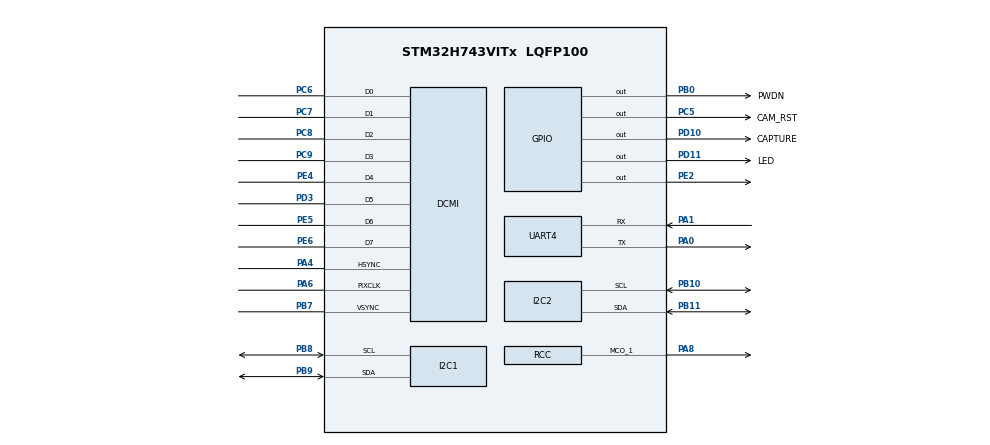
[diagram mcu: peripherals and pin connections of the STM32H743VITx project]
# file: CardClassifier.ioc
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CORTEX_M7.CPU_DCache=Enabled
CORTEX_M7.CPU_ICache=Enabled
CORTEX_M7.default_mode_Activation=1
DCMI.PCKPolarity=DCMI_PCKPOLARITY_RISING
DCMI.VSPolarity=DCMI_VSPOLARITY_HIGH
Dma.DCMI.0.Direction=DMA_PERIPH_TO_MEMORY
Dma.DCMI.0.EventEnable=DISABLE
Dma.DCMI.0.FIFOMode=DMA_FIFOMODE_DISABLE
Dma.DCMI.0.Instance=DMA1_Stream0
Dma.DCMI.0.MemDataAlignment=DMA_MDATAALIGN_WORD
Dma.DCMI.0.MemInc=DMA_MINC_ENABLE
Dma.DCMI.0.Mode=DMA_NORMAL
Dma.DCMI.0.PeriphDataAlignment=DMA_PDATAALIGN_WORD
Dma.DCMI.0.PeriphInc=DMA_PINC_DISABLE
Dma.DCMI.0.Polarity=HAL_DMAMUX_REQ_GEN_RISING
Dma.DCMI.0.Priority=DMA_PRIORITY_VERY_HIGH
Dma.DCMI.0.RequestNumber=1
Dma.DCMI.0.SignalID=NONE
Dma.DCMI.0.SyncEnable=DISABLE
Dma.DCMI.0.SyncPolarity=HAL_DMAMUX_SYNC_NO_EVENT
Dma.DCMI.0.SyncRequestNumber=1
Dma.DCMI.0.SyncSignalID=NONE
Dma.Request0=DCMI
I2C1.Timing=0x00707CBB
I2C2.Timing=0x00707CBB
Mcu.Family=STM32H7
Mcu.Name=STM32H743VITx
Mcu.Package=LQFP100
NVIC.DCMI_IRQn=true\:0\:0\:false\:false\:true\:true\:true\:true
NVIC.DMA1_Stream0_IRQn=true\:0\:0\:false\:false\:true\:false\:true\:true
NVIC.PriorityGroup=NVIC_PRIORITYGROUP_4
PA0.Mode=Asynchronous
PA0.Signal=UART4_TX
PA1.Mode=Asynchronous
PA1.Signal=UART4_RX
PA4.GPIO_PuPd=GPIO_PULLDOWN
PA4.GPIO_Speed=GPIO_SPEED_FREQ_VERY_HIGH
PA4.Mode=Slave_8_bits_External_Synchro
PA4.Signal=DCMI_HSYNC
PA6.GPIO_PuPd=GPIO_PULLDOWN
PA6.GPIO_Speed=GPIO_SPEED_FREQ_VERY_HIGH
PA6.Mode=Slave_8_bits_External_Synchro
PA6.Signal=DCMI_PIXCLK
PA8.Mode=Clock-out-1
PA8.Signal=RCC_MCO_1
PB0.GPIO_Label=PWDN
PB0.PinState=GPIO_PIN_SET
PB0.Signal=GPIO_Output
PB10.GPIO_Pu=GPIO_NOPULL
PB10.Mode=I2C
PB10.Signal=I2C2_SCL
PB11.GPIO_Pu=GPIO_NOPULL
PB11.Mode=I2C
PB11.Signal=I2C2_SDA
PB7.GPIO_PuPd=GPIO_PULLDOWN
PB7.GPIO_Speed=GPIO_SPEED_FREQ_VERY_HIGH
PB7.Mode=Slave_8_bits_External_Synchro
PB7.Signal=DCMI_VSYNC
PB8.GPIO_Pu=GPIO_PULLUP
PB8.Mode=I2C
PB8.Signal=I2C1_SCL
PB9.GPIO_Pu=GPIO_PULLUP
PB9.Mode=I2C
PB9.Signal=I2C1_SDA
PC5.GPIO_Label=CAM_RST
PC5.Signal=GPIO_Output
PC6.GPIO_PuPd=GPIO_PULLDOWN
PC6.GPIO_Speed=GPIO_SPEED_FREQ_VERY_HIGH
PC6.Mode=Slave_8_bits_External_Synchro
PC6.Signal=DCMI_D0
PC7.GPIO_PuPd=GPIO_PULLDOWN
PC7.GPIO_Speed=GPIO_SPEED_FREQ_VERY_HIGH
PC7.Mode=Slave_8_bits_External_Synchro
PC7.Signal=DCMI_D1
PC8.GPIO_PuPd=GPIO_PULLDOWN
PC8.GPIO_Speed=GPIO_SPEED_FREQ_VERY_HIGH
PC8.Mode=Slave_8_bits_External_Synchro
PC8.Signal=DCMI_D2
PC9.GPIO_PuPd=GPIO_PULLDOWN
PC9.GPIO_Speed=GPIO_SPEED_FREQ_VERY_HIGH
PC9.Mode=Slave_8_bits_External_Synchro
PC9.Signal=DCMI_D3
PD10.GPIO_Label=CAPTURE
PD10.Signal=GPIO_Output
PD11.GPIO_Label=LED
PD11.Signal=GPIO_Output
PD3.GPIO_PuPd=GPIO_PULLDOWN
PD3.GPIO_Speed=GPIO_SPEED_FREQ_VERY_HIGH
PD3.Mode=Slave_8_bits_External_Synchro
PD3.Signal=DCMI_D5
PE2.Signal=GPIO_Output
PE4.GPIO_PuPd=GPIO_PULLDOWN
PE4.GPIO_Speed=GPIO_SPEED_FREQ_VERY_HIGH
PE4.Mode=Slave_8_bits_External_Synchro
PE4.Signal=DCMI_D4
PE5.GPIO_PuPd=GPIO_PULLDOWN
PE5.GPIO_Speed=GPIO_SPEED_FREQ_VERY_HIGH
PE5.Mode=Slave_8_bits_External_Synchro
PE5.Signal=DCMI_D6
PE6.GPIO_PuPd=GPIO_PULLDOWN
PE6.GPIO_Speed=GPIO_SPEED_FREQ_VERY_HIGH
PE6.Mode=Slave_8_bits_External_Synchro
PE6.Signal=DCMI_D7
PH0-OSC_IN\ (PH0).Mode=HSE-External-Clock-Source
PH0-OSC_IN\ (PH0).Signal=RCC_OSC_IN
ProjectManager.HeapSize=0x800
ProjectManager.StackSize=0x800
ProjectManager.TargetToolchain=STM32CubeIDE
RCC.ADCFreq_Value=16125000
RCC.APB1CLKDivider=RCC_HCLK_DIV4
RCC.APB1Freq_Value=120000000
RCC.APB2CLKDivider=RCC_HCLK_DIV2
RCC.APB2Freq_Value=120000000
RCC.APB3Freq_Value=120000000
RCC.APB4Freq_Value=120000000
RCC.CortexFreq_Value=480000000
RCC.D1PPRE=RCC_APB3_DIV2
RCC.D2PPRE1=RCC_APB1_DIV2
RCC.D2PPRE2=RCC_APB2_DIV2
RCC.D3PPRE=RCC_APB4_DIV2
RCC.DIVM1=4
RCC.DIVM3=4
RCC.DIVN1=480
RCC.DIVN3=480
RCC.DIVQ1=20
RCC.DIVQ3=8
RCC.FLatency=FLASH_LATENCY_4
RCC.HCLKFreq_Value=240000000
RCC.HPRE=RCC_HCLK_DIV2
RCC.HSE_VALUE=8000000
RCC.PLLM=25
RCC.PLLMUL=RCC_PLL_MUL9
RCC.PLLN=432
RCC.PLLQ=9
RCC.PLLSourceVirtual=RCC_PLLSOURCE_HSE
RCC.PRESCALERUSB=RCC_USBCLKSOURCE_PLL_DIV1_5
RCC.PWR_Regulator_Voltage_Scale=PWR_REGULATOR_VOLTAGE_SCALE0
RCC.RCC_MCODiv1=RCC_MCODIV_3
RCC.SYSCLKFreq_VALUE=480000000
RCC.SYSCLKSource=RCC_SYSCLKSOURCE_PLLCLK
RCC.SYSCLKSourceVirtual=RCC_SYSCLKSOURCE_PLLCLK
RCC.USBFreq_Value=48000000
STMicroelectronics.X-CUBE-AI.8.1.0.ActivationBufferSizeList=199676
STMicroelectronics.X-CUBE-AI.8.1.0.ActivationBuffers=pool0
STMicroelectronics.X-CUBE-AI.8.1.0.ActivationNames=pool0
STMicroelectronics.X-CUBE-AI.8.1.0.ActivationSizes=AI_NETWORK_DATA_ACTIVATION_1_SIZE
STMicroelectronics.X-CUBE-AI.8.1.0.ApplicationCcDeviceJjApplication=ApplicationTemplate
STMicroelectronics.X-CUBE-AI.8.1.0.HeapSize=0x800
STMicroelectronics.X-CUBE-AI.8.1.0.InternalRamActivationBufferMaxSize=AI_NETWORK_DATA_ACTIVATIONS_SIZE
STMicroelectronics.X-CUBE-AI.8.1.0.LatestDirectoryUsed-eb934d6c53bd655998cb05dfb2e9a394d111bbf30eaa32c1144144a35eb904d4=\\\\ad.uillinois.edu\\engr-ews\\ryfu2\\Desktop
STMicroelectronics.X-CUBE-AI.8.1.0.MaximumNumberOfInputLayer=1
STMicroelectronics.X-CUBE-AI.8.1.0.MaximumNumberOfOutputLayer=1
STMicroelectronics.X-CUBE-AI.8.1.0.MaximumSizeOfInputLayer=1
STMicroelectronics.X-CUBE-AI.8.1.0.MaximumSizeOfOutputLayer=1
STMicroelectronics.X-CUBE-AI.8.1.0.ModelActualCompression-eb934d6c53bd655998cb05dfb2e9a394d111bbf30eaa32c1144144a35eb904d4=0.0
STMicroelectronics.X-CUBE-AI.8.1.0.ModelCompression-eb934d6c53bd655998cb05dfb2e9a394d111bbf30eaa32c1144144a35eb904d4=None
STMicroelectronics.X-CUBE-AI.8.1.0.ModelFlashOccupation-eb934d6c53bd655998cb05dfb2e9a394d111bbf30eaa32c1144144a35eb904d4=414242
STMicroelectronics.X-CUBE-AI.8.1.0.ModelHashList=eb934d6c53bd655998cb05dfb2e9a394d111bbf30eaa32c1144144a35eb904d4
STMicroelectronics.X-CUBE-AI.8.1.0.ModelKind-eb934d6c53bd655998cb05dfb2e9a394d111bbf30eaa32c1144144a35eb904d4=TFLITE
STMicroelectronics.X-CUBE-AI.8.1.0.ModelMacc-eb934d6c53bd655998cb05dfb2e9a394d111bbf30eaa32c1144144a35eb904d4=3452608
STMicroelectronics.X-CUBE-AI.8.1.0.ModelName-eb934d6c53bd655998cb05dfb2e9a394d111bbf30eaa32c1144144a35eb904d4=network
STMicroelectronics.X-CUBE-AI.8.1.0.ModelNameList=network
STMicroelectronics.X-CUBE-AI.8.1.0.ModelRamOccupation-eb934d6c53bd655998cb05dfb2e9a394d111bbf30eaa32c1144144a35eb904d4=199676
STMicroelectronics.X-CUBE-AI.8.1.0.ModelStructureFile-eb934d6c53bd655998cb05dfb2e9a394d111bbf30eaa32c1144144a35eb904d4=\\\\ad.uillinois.edu\\engr-ews\\ryfu2\\Desktop\\model_color.tflite
STMicroelectronics.X-CUBE-AI.8.1.0.ModelType-eb934d6c53bd655998cb05dfb2e9a394d111bbf30eaa32c1144144a35eb904d4=STM32Cube.AI runtime
STMicroelectronics.X-CUBE-AI.8.1.0.ReadyForCodeGeneration=true
STMicroelectronics.X-CUBE-AI.8.1.0.StackSize=0x800
STMicroelectronics.X-CUBE-AI.8.1.0.WorkingBufferStartAddrList=0xFFFFFFFF
STMicroelectronics.X-CUBE-AI.8.1.0.XAaCUBEAaAICcArtificialOoIntelligenceJjCore=true
STMicroelectronics.X-CUBE-AI.8.1.0.copyWeightToRam=false
STMicroelectronics.X-CUBE-AI.8.1.0.customLayerConfigEnabled=false
STMicroelectronics.X-CUBE-AI.8.1.0.noOnnxIoTranspose=false
STMicroelectronics.X-CUBE-AI.8.1.0.useInputAllocation=true
STMicroelectronics.X-CUBE-AI.8.1.0.useOutputAllocation=true
VP_CRC_VS_CRC.Mode=CRC_Activate
VP_STMicroelectronics.X-CUBE-AI_VS_ArtificialOoIntelligenceJjXAaCUBEAaAI_8.1.0.Mode=ArtificialOoIntelligenceJjXAaCUBEAaAI
VP_STMicroelectronics.X-CUBE-AI_VS_DeviceJjApplication_8.1.0.Mode=DeviceJjApplication
board=custom

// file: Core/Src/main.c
/* USER CODE BEGIN Header */
/**
  ******************************************************************************
  * @file           : main.c
  * @brief          : Main program body
  ******************************************************************************
  * @attention
  *
  * Copyright (c) 2024 STMicroelectronics.
  * All rights reserved.
  *
  * This software is licensed under terms that can be found in the LICENSE file
  * in the root directory of this software component.
  * If no LICENSE file comes with this software, it is provided AS-IS.
  *
  ******************************************************************************
  */
/* USER CODE END Header */
#include "main.h"
#include "app_x-cube-ai.h"

CRC_HandleTypeDef hcrc;

DCMI_HandleTypeDef hdcmi;
DMA_HandleTypeDef hdma_dcmi;

I2C_HandleTypeDef hi2c1;
I2C_HandleTypeDef hi2c2;

UART_HandleTypeDef huart4;

void SystemClock_Config(void);
static void MX_GPIO_Init(void);
static void MX_DMA_Init(void);
static void MX_DCMI_Init(void);
static void MX_I2C1_Init(void);
static void MX_I2C2_Init(void);
static void MX_UART4_Init(void);
static void MX_CRC_Init(void);

/* USER CODE BEGIN 0 */
uint32_t* imagedata[176 * 144 /2];
uint32_t* imagedata128[128*128/2];
/* USER CODE END 0 */

int main(void)
{

  /* Enable the CPU Cache */

  /* Enable I-Cache---------------------------------------------------------*/
//  SCB_EnableICache();

  /* Enable D-Cache---------------------------------------------------------*/
//  SCB_EnableDCache();

  /* MCU Configuration--------------------------------------------------------*/

  /* Reset of all peripherals, Initializes the Flash interface and the Systick. */
  HAL_Init();

  /* Configure the system clock */
  SystemClock_Config();

  /* Initialize all configured peripherals */
  MX_GPIO_Init();
  MX_DMA_Init();
  MX_DCMI_Init();
  MX_I2C1_Init();
  MX_I2C2_Init();
  MX_UART4_Init();
  MX_CRC_Init();
  MX_X_CUBE_AI_Init();
  /* USER CODE BEGIN 2 */

  ///// START OF LCD //////

  lcd_init(&hi2c2);
  lcd_clear();
  lcd_send_string("Processing...");
//  lcd_clear();
//  lcd_send_string("81 loaded to x15");
  ///// END OF LCD /////

  ///// START OF OV7670 CAMERA /////
//  ov7670_init(&hi2c1);
//
//  // TEST WRITING 0x81 to 0x15
//  HAL_Delay(100);
//  ov7670_write(0x15,0x81);

  uint8_t data[100];
  char buffer [100];

  ov7670_read(0x15,data);
  sprintf(buffer, "Addr:0x15; D:%x;", *data);

  // CONFIG CAM REGISTERS
  ov7670_init(&hi2c1);
  ov7670_write(0x12,0x0C);
  ov7670_write(0x40,0xD0); //Enable RGB
  ov7670_write(0x13,0x20);// Enable banding filter
  ov7670_write(0x3B,0x12);// Banding filter settings
  //  ov7670_write(0x10,0x40); // Adjust Exposure time
  //  ov7670_write(0x13,0x00);// Disable fast AGC/AEC algorithm and banding filter

  //Color Matrix
  ov7670_write(0x4f,0x80);
  ov7670_write(0x50,0x80);
  ov7670_write(0x51,0x00);
  ov7670_write(0x52,0x22);
  ov7670_write(0x53,0x5E);
  ov7670_write(0x54,0x80);
  ov7670_write(0x58,0x9E);
  HAL_GPIO_TogglePin (GPIOD, GPIO_PIN_11);
  // PRINT IMAGE LOG
  uint32_t imagedata[176 * 144 /2];
  for (int i = 0; i < 176*144 / 2; ++i) {
    imagedata[i] = 0;
  }

  sprintf(buffer, "imagedata address: %x\r\n", imagedata); //24073924
  HAL_UART_Transmit(&huart4,buffer,strlen(buffer),10);
  imagedata[0] = 0xFF; // Check if index 0 properly overwritten
  ov7670_startCap(imagedata);

  Resize_to_128(imagedata, imagedata128);
//  for (int i = 0; i < 128*128 / 2; ++i) {
//  	sprintf(buffer, "index: %d, data: %x\r\n",i, imagedata128[i]);
//  	HAL_UART_Transmit(&huart4,buffer,strlen(buffer),10);
//  	HAL_Delay(20);
//  }
  ///// END OF OV7670 CAMERA /////
   MX_X_CUBE_AI_Process();
  /* USER CODE END 2 */

  /* Infinite loop */
  while (1)
  {

  }
}

void SystemClock_Config(void)
{
  RCC_OscInitTypeDef RCC_OscInitStruct = {0};
  RCC_ClkInitTypeDef RCC_ClkInitStruct = {0};

  /** Supply configuration update enable
  */
  HAL_PWREx_ConfigSupply(PWR_LDO_SUPPLY);

  /** Configure the main internal regulator output voltage
  */
  __HAL_PWR_VOLTAGESCALING_CONFIG(PWR_REGULATOR_VOLTAGE_SCALE3);

  while(!__HAL_PWR_GET_FLAG(PWR_FLAG_VOSRDY)) {}

  /** Initializes the RCC Oscillators according to the specified parameters
  * in the RCC_OscInitTypeDef structure.
  */
  RCC_OscInitStruct.OscillatorType = RCC_OSCILLATORTYPE_HSI;
  RCC_OscInitStruct.HSIState = RCC_HSI_DIV1;
  RCC_OscInitStruct.HSICalibrationValue = RCC_HSICALIBRATION_DEFAULT;
  RCC_OscInitStruct.PLL.PLLState = RCC_PLL_NONE;
  if (HAL_RCC_OscConfig(&RCC_OscInitStruct) != HAL_OK)
  {
    Error_Handler();
  }

  /** Initializes the CPU, AHB and APB buses clocks
  */
  RCC_ClkInitStruct.ClockType = RCC_CLOCKTYPE_HCLK|RCC_CLOCKTYPE_SYSCLK
                              |RCC_CLOCKTYPE_PCLK1|RCC_CLOCKTYPE_PCLK2
                              |RCC_CLOCKTYPE_D3PCLK1|RCC_CLOCKTYPE_D1PCLK1;
  RCC_ClkInitStruct.SYSCLKSource = RCC_SYSCLKSOURCE_HSI;
  RCC_ClkInitStruct.SYSCLKDivider = RCC_SYSCLK_DIV1;
  RCC_ClkInitStruct.AHBCLKDivider = RCC_HCLK_DIV1;
  RCC_ClkInitStruct.APB3CLKDivider = RCC_APB3_DIV1;
  RCC_ClkInitStruct.APB1CLKDivider = RCC_APB1_DIV2;
  RCC_ClkInitStruct.APB2CLKDivider = RCC_APB2_DIV1;
  RCC_ClkInitStruct.APB4CLKDivider = RCC_APB4_DIV1;

  if (HAL_RCC_ClockConfig(&RCC_ClkInitStruct, FLASH_LATENCY_1) != HAL_OK)
  {
    Error_Handler();
  }
  HAL_RCC_MCOConfig(RCC_MCO1, RCC_MCO1SOURCE_HSI, RCC_MCODIV_3);
}

static void MX_CRC_Init(void)
{

  hcrc.Instance = CRC;
  hcrc.Init.DefaultPolynomialUse = DEFAULT_POLYNOMIAL_ENABLE;
  hcrc.Init.DefaultInitValueUse = DEFAULT_INIT_VALUE_ENABLE;
  hcrc.Init.InputDataInversionMode = CRC_INPUTDATA_INVERSION_NONE;
  hcrc.Init.OutputDataInversionMode = CRC_OUTPUTDATA_INVERSION_DISABLE;
  hcrc.InputDataFormat = CRC_INPUTDATA_FORMAT_BYTES;
  if (HAL_CRC_Init(&hcrc) != HAL_OK)
  {
    Error_Handler();
  }

}

static void MX_DCMI_Init(void)
{

  hdcmi.Instance = DCMI;
  hdcmi.Init.SynchroMode = DCMI_SYNCHRO_HARDWARE;
  hdcmi.Init.PCKPolarity = DCMI_PCKPOLARITY_RISING;
  hdcmi.Init.VSPolarity = DCMI_VSPOLARITY_HIGH;
  hdcmi.Init.HSPolarity = DCMI_HSPOLARITY_LOW;
  hdcmi.Init.CaptureRate = DCMI_CR_ALL_FRAME;
  hdcmi.Init.ExtendedDataMode = DCMI_EXTEND_DATA_8B;
  hdcmi.Init.JPEGMode = DCMI_JPEG_DISABLE;
  hdcmi.Init.ByteSelectMode = DCMI_BSM_ALL;
  hdcmi.Init.ByteSelectStart = DCMI_OEBS_ODD;
  hdcmi.Init.LineSelectMode = DCMI_LSM_ALL;
  hdcmi.Init.LineSelectStart = DCMI_OELS_ODD;
  if (HAL_DCMI_Init(&hdcmi) != HAL_OK)
  {
    Error_Handler();
  }

}

static void MX_I2C1_Init(void)
{

  hi2c1.Instance = I2C1;
  hi2c1.Init.Timing = 0x00707CBB;
  hi2c1.Init.OwnAddress1 = 0;
  hi2c1.Init.AddressingMode = I2C_ADDRESSINGMODE_7BIT;
  hi2c1.Init.DualAddressMode = I2C_DUALADDRESS_DISABLE;
  hi2c1.Init.OwnAddress2 = 0;
  hi2c1.Init.OwnAddress2Masks = I2C_OA2_NOMASK;
  hi2c1.Init.GeneralCallMode = I2C_GENERALCALL_DISABLE;
  hi2c1.Init.NoStretchMode = I2C_NOSTRETCH_DISABLE;
  if (HAL_I2C_Init(&hi2c1) != HAL_OK)
  {
    Error_Handler();
  }

  /** Configure Analogue filter
  */
  if (HAL_I2CEx_ConfigAnalogFilter(&hi2c1, I2C_ANALOGFILTER_ENABLE) != HAL_OK)
  {
    Error_Handler();
  }

  /** Configure Digital filter
  */
  if (HAL_I2CEx_ConfigDigitalFilter(&hi2c1, 0) != HAL_OK)
  {
    Error_Handler();
  }

}

static void MX_I2C2_Init(void)
{

  hi2c2.Instance = I2C2;
  hi2c2.Init.Timing = 0x00707CBB;
  hi2c2.Init.OwnAddress1 = 0;
  hi2c2.Init.AddressingMode = I2C_ADDRESSINGMODE_7BIT;
  hi2c2.Init.DualAddressMode = I2C_DUALADDRESS_DISABLE;
  hi2c2.Init.OwnAddress2 = 0;
  hi2c2.Init.OwnAddress2Masks = I2C_OA2_NOMASK;
  hi2c2.Init.GeneralCallMode = I2C_GENERALCALL_DISABLE;
  hi2c2.Init.NoStretchMode = I2C_NOSTRETCH_DISABLE;
  if (HAL_I2C_Init(&hi2c2) != HAL_OK)
  {
    Error_Handler();
  }

  /** Configure Analogue filter
  */
  if (HAL_I2CEx_ConfigAnalogFilter(&hi2c2, I2C_ANALOGFILTER_ENABLE) != HAL_OK)
  {
    Error_Handler();
  }

  /** Configure Digital filter
  */
  if (HAL_I2CEx_ConfigDigitalFilter(&hi2c2, 0) != HAL_OK)
  {
    Error_Handler();
  }

}

static void MX_UART4_Init(void)
{

  huart4.Instance = UART4;
  huart4.Init.BaudRate = 115200;
  huart4.Init.WordLength = UART_WORDLENGTH_8B;
  huart4.Init.StopBits = UART_STOPBITS_1;
  huart4.Init.Parity = UART_PARITY_NONE;
  huart4.Init.Mode = UART_MODE_TX_RX;
  huart4.Init.HwFlowCtl = UART_HWCONTROL_NONE;
  huart4.Init.OverSampling = UART_OVERSAMPLING_16;
  huart4.Init.OneBitSampling = UART_ONE_BIT_SAMPLE_DISABLE;
  huart4.Init.ClockPrescaler = UART_PRESCALER_DIV1;
  huart4.AdvancedInit.AdvFeatureInit = UART_ADVFEATURE_NO_INIT;
  if (HAL_UART_Init(&huart4) != HAL_OK)
  {
    Error_Handler();
  }
  if (HAL_UARTEx_SetTxFifoThreshold(&huart4, UART_TXFIFO_THRESHOLD_1_8) != HAL_OK)
  {
    Error_Handler();
  }
  if (HAL_UARTEx_SetRxFifoThreshold(&huart4, UART_RXFIFO_THRESHOLD_1_8) != HAL_OK)
  {
    Error_Handler();
  }
  if (HAL_UARTEx_DisableFifoMode(&huart4) != HAL_OK)
  {
    Error_Handler();
  }

}

static void MX_DMA_Init(void)
{

  /* DMA controller clock enable */
  __HAL_RCC_DMA1_CLK_ENABLE();

  /* DMA interrupt init */
  /* DMA1_Stream0_IRQn interrupt configuration */
  HAL_NVIC_SetPriority(DMA1_Stream0_IRQn, 0, 0);
  HAL_NVIC_EnableIRQ(DMA1_Stream0_IRQn);

}

static void MX_GPIO_Init(void)
{
  GPIO_InitTypeDef GPIO_InitStruct = {0};

  /* GPIO Ports Clock Enable */
  __HAL_RCC_GPIOE_CLK_ENABLE();
  __HAL_RCC_GPIOH_CLK_ENABLE();
  __HAL_RCC_GPIOA_CLK_ENABLE();
  __HAL_RCC_GPIOC_CLK_ENABLE();
  __HAL_RCC_GPIOB_CLK_ENABLE();
  __HAL_RCC_GPIOD_CLK_ENABLE();

  /*Configure GPIO pin Output Level */
  HAL_GPIO_WritePin(GPIOE, GPIO_PIN_2, GPIO_PIN_RESET);

  /*Configure GPIO pin Output Level */
  HAL_GPIO_WritePin(CAM_RST_GPIO_Port, CAM_RST_Pin, GPIO_PIN_RESET);

  /*Configure GPIO pin Output Level */
  HAL_GPIO_WritePin(PWDN_GPIO_Port, PWDN_Pin, GPIO_PIN_SET);

  /*Configure GPIO pin Output Level */
  HAL_GPIO_WritePin(GPIOD, CAPTURE_Pin|LED_Pin, GPIO_PIN_RESET);

  /*Configure GPIO pin : PE2 */
  GPIO_InitStruct.Pin = GPIO_PIN_2;
  GPIO_InitStruct.Mode = GPIO_MODE_OUTPUT_PP;
  GPIO_InitStruct.Pull = GPIO_NOPULL;
  GPIO_InitStruct.Speed = GPIO_SPEED_FREQ_LOW;
  HAL_GPIO_Init(GPIOE, &GPIO_InitStruct);

  /*Configure GPIO pin : CAM_RST_Pin */
  GPIO_InitStruct.Pin = CAM_RST_Pin;
  GPIO_InitStruct.Mode = GPIO_MODE_OUTPUT_PP;
  GPIO_InitStruct.Pull = GPIO_NOPULL;
  GPIO_InitStruct.Speed = GPIO_SPEED_FREQ_LOW;
  HAL_GPIO_Init(CAM_RST_GPIO_Port, &GPIO_InitStruct);

  /*Configure GPIO pin : PWDN_Pin */
  GPIO_InitStruct.Pin = PWDN_Pin;
  GPIO_InitStruct.Mode = GPIO_MODE_OUTPUT_PP;
  GPIO_InitStruct.Pull = GPIO_NOPULL;
  GPIO_InitStruct.Speed = GPIO_SPEED_FREQ_LOW;
  HAL_GPIO_Init(PWDN_GPIO_Port, &GPIO_InitStruct);

  /*Configure GPIO pins : CAPTURE_Pin LED_Pin */
  GPIO_InitStruct.Pin = CAPTURE_Pin|LED_Pin;
  GPIO_InitStruct.Mode = GPIO_MODE_OUTPUT_PP;
  GPIO_InitStruct.Pull = GPIO_NOPULL;
  GPIO_InitStruct.Speed = GPIO_SPEED_FREQ_LOW;
  HAL_GPIO_Init(GPIOD, &GPIO_InitStruct);

  /*Configure GPIO pin : PA8 */
  GPIO_InitStruct.Pin = GPIO_PIN_8;
  GPIO_InitStruct.Mode = GPIO_MODE_AF_PP;
  GPIO_InitStruct.Pull = GPIO_NOPULL;
  GPIO_InitStruct.Speed = GPIO_SPEED_FREQ_LOW;
  GPIO_InitStruct.Alternate = GPIO_AF0_MCO;
  HAL_GPIO_Init(GPIOA, &GPIO_InitStruct);

}

void Error_Handler(void)
{
  __disable_irq();
  while (1)
  {
  }
}
